# Generated by FakeRAM 2.0
VERSION 5.7 ;
BUSBITCHARS "[]" ;
PROPERTYDEFINITIONS
  MACRO width INTEGER ;
  MACRO depth INTEGER ;
  MACRO banks INTEGER ;
END PROPERTYDEFINITIONS
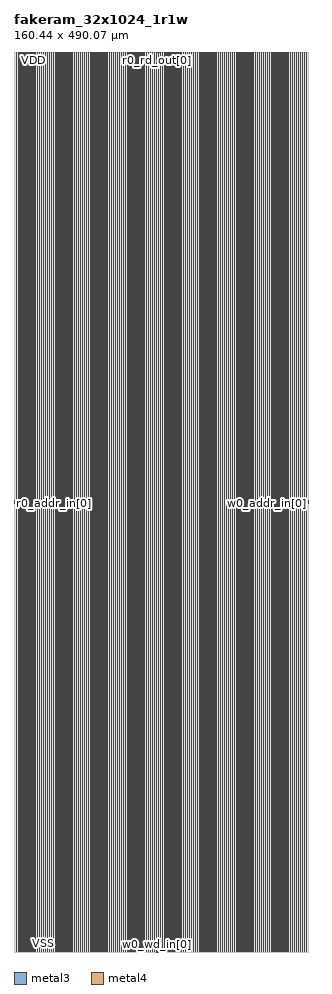
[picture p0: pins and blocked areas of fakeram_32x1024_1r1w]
MACRO fakeram_32x1024_1r1w
  PROPERTY width 32 ;
  PROPERTY depth 1024 ;
  PROPERTY banks 1 ;
  FOREIGN fakeram_32x1024_1r1w 0 0 ;
  SYMMETRY X Y R90 ;
  SIZE 160.440 BY 490.070 ;
  CLASS BLOCK ;
  PIN r0_addr_in[0]
    DIRECTION INPUT ;
    USE SIGNAL ;
    SHAPE ABUTMENT ;
    PORT
      LAYER metal3 ;
      RECT 0.000 244.020 0.070 244.090 ;
    END
  END r0_addr_in[0]
  PIN r0_addr_in[1]
    DIRECTION INPUT ;
    USE SIGNAL ;
    SHAPE ABUTMENT ;
    PORT
      LAYER metal3 ;
      RECT 0.000 244.160 0.070 244.230 ;
    END
  END r0_addr_in[1]
  PIN r0_addr_in[2]
    DIRECTION INPUT ;
    USE SIGNAL ;
    SHAPE ABUTMENT ;
    PORT
      LAYER metal3 ;
      RECT 0.000 244.300 0.070 244.370 ;
    END
  END r0_addr_in[2]
  PIN r0_addr_in[3]
    DIRECTION INPUT ;
    USE SIGNAL ;
    SHAPE ABUTMENT ;
    PORT
      LAYER metal3 ;
      RECT 0.000 244.440 0.070 244.510 ;
    END
  END r0_addr_in[3]
  PIN r0_addr_in[4]
    DIRECTION INPUT ;
    USE SIGNAL ;
    SHAPE ABUTMENT ;
    PORT
      LAYER metal3 ;
      RECT 0.000 244.580 0.070 244.650 ;
    END
  END r0_addr_in[4]
  PIN r0_addr_in[5]
    DIRECTION INPUT ;
    USE SIGNAL ;
    SHAPE ABUTMENT ;
    PORT
      LAYER metal3 ;
      RECT 0.000 244.720 0.070 244.790 ;
    END
  END r0_addr_in[5]
  PIN r0_addr_in[6]
    DIRECTION INPUT ;
    USE SIGNAL ;
    SHAPE ABUTMENT ;
    PORT
      LAYER metal3 ;
      RECT 0.000 244.860 0.070 244.930 ;
    END
  END r0_addr_in[6]
  PIN r0_addr_in[7]
    DIRECTION INPUT ;
    USE SIGNAL ;
    SHAPE ABUTMENT ;
    PORT
      LAYER metal3 ;
      RECT 0.000 245.000 0.070 245.070 ;
    END
  END r0_addr_in[7]
  PIN r0_addr_in[8]
    DIRECTION INPUT ;
    USE SIGNAL ;
    SHAPE ABUTMENT ;
    PORT
      LAYER metal3 ;
      RECT 0.000 245.140 0.070 245.210 ;
    END
  END r0_addr_in[8]
  PIN r0_addr_in[9]
    DIRECTION INPUT ;
    USE SIGNAL ;
    SHAPE ABUTMENT ;
    PORT
      LAYER metal3 ;
      RECT 0.000 245.280 0.070 245.350 ;
    END
  END r0_addr_in[9]
  PIN r0_ce_in
    DIRECTION INPUT ;
    USE SIGNAL ;
    SHAPE ABUTMENT ;
    PORT
      LAYER metal3 ;
      RECT 0.000 245.560 0.070 245.630 ;
    END
  END r0_ce_in
  PIN r0_clk
    DIRECTION INPUT ;
    USE SIGNAL ;
    SHAPE ABUTMENT ;
    PORT
      LAYER metal3 ;
      RECT 0.000 245.700 0.070 245.770 ;
    END
  END r0_clk
  PIN r0_rd_out[0]
    DIRECTION OUTPUT ;
    USE SIGNAL ;
    SHAPE ABUTMENT ;
    PORT
      LAYER metal3 ;
      RECT 77.805 490.000 77.875 490.070 ;
    END
  END r0_rd_out[0]
  PIN r0_rd_out[1]
    DIRECTION OUTPUT ;
    USE SIGNAL ;
    SHAPE ABUTMENT ;
    PORT
      LAYER metal3 ;
      RECT 77.945 490.000 78.015 490.070 ;
    END
  END r0_rd_out[1]
  PIN r0_rd_out[2]
    DIRECTION OUTPUT ;
    USE SIGNAL ;
    SHAPE ABUTMENT ;
    PORT
      LAYER metal3 ;
      RECT 78.085 490.000 78.155 490.070 ;
    END
  END r0_rd_out[2]
  PIN r0_rd_out[3]
    DIRECTION OUTPUT ;
    USE SIGNAL ;
    SHAPE ABUTMENT ;
    PORT
      LAYER metal3 ;
      RECT 78.225 490.000 78.295 490.070 ;
    END
  END r0_rd_out[3]
  PIN r0_rd_out[4]
    DIRECTION OUTPUT ;
    USE SIGNAL ;
    SHAPE ABUTMENT ;
    PORT
      LAYER metal3 ;
      RECT 78.365 490.000 78.435 490.070 ;
    END
  END r0_rd_out[4]
  PIN r0_rd_out[5]
    DIRECTION OUTPUT ;
    USE SIGNAL ;
    SHAPE ABUTMENT ;
    PORT
      LAYER metal3 ;
      RECT 78.505 490.000 78.575 490.070 ;
    END
  END r0_rd_out[5]
  PIN r0_rd_out[6]
    DIRECTION OUTPUT ;
    USE SIGNAL ;
    SHAPE ABUTMENT ;
    PORT
      LAYER metal3 ;
      RECT 78.645 490.000 78.715 490.070 ;
    END
  END r0_rd_out[6]
  PIN r0_rd_out[7]
    DIRECTION OUTPUT ;
    USE SIGNAL ;
    SHAPE ABUTMENT ;
    PORT
      LAYER metal3 ;
      RECT 78.785 490.000 78.855 490.070 ;
    END
  END r0_rd_out[7]
  PIN r0_rd_out[8]
    DIRECTION OUTPUT ;
    USE SIGNAL ;
    SHAPE ABUTMENT ;
    PORT
      LAYER metal3 ;
      RECT 78.925 490.000 78.995 490.070 ;
    END
  END r0_rd_out[8]
  PIN r0_rd_out[9]
    DIRECTION OUTPUT ;
    USE SIGNAL ;
    SHAPE ABUTMENT ;
    PORT
      LAYER metal3 ;
      RECT 79.065 490.000 79.135 490.070 ;
    END
  END r0_rd_out[9]
  PIN r0_rd_out[10]
    DIRECTION OUTPUT ;
    USE SIGNAL ;
    SHAPE ABUTMENT ;
    PORT
      LAYER metal3 ;
      RECT 79.205 490.000 79.275 490.070 ;
    END
  END r0_rd_out[10]
  PIN r0_rd_out[11]
    DIRECTION OUTPUT ;
    USE SIGNAL ;
    SHAPE ABUTMENT ;
    PORT
      LAYER metal3 ;
      RECT 79.345 490.000 79.415 490.070 ;
    END
  END r0_rd_out[11]
  PIN r0_rd_out[12]
    DIRECTION OUTPUT ;
    USE SIGNAL ;
    SHAPE ABUTMENT ;
    PORT
      LAYER metal3 ;
      RECT 79.485 490.000 79.555 490.070 ;
    END
  END r0_rd_out[12]
  PIN r0_rd_out[13]
    DIRECTION OUTPUT ;
    USE SIGNAL ;
    SHAPE ABUTMENT ;
    PORT
      LAYER metal3 ;
      RECT 79.625 490.000 79.695 490.070 ;
    END
  END r0_rd_out[13]
  PIN r0_rd_out[14]
    DIRECTION OUTPUT ;
    USE SIGNAL ;
    SHAPE ABUTMENT ;
    PORT
      LAYER metal3 ;
      RECT 79.765 490.000 79.835 490.070 ;
    END
  END r0_rd_out[14]
  PIN r0_rd_out[15]
    DIRECTION OUTPUT ;
    USE SIGNAL ;
    SHAPE ABUTMENT ;
    PORT
      LAYER metal3 ;
      RECT 79.905 490.000 79.975 490.070 ;
    END
  END r0_rd_out[15]
  PIN r0_rd_out[16]
    DIRECTION OUTPUT ;
    USE SIGNAL ;
    SHAPE ABUTMENT ;
    PORT
      LAYER metal3 ;
      RECT 80.045 490.000 80.115 490.070 ;
    END
  END r0_rd_out[16]
  PIN r0_rd_out[17]
    DIRECTION OUTPUT ;
    USE SIGNAL ;
    SHAPE ABUTMENT ;
    PORT
      LAYER metal3 ;
      RECT 80.185 490.000 80.255 490.070 ;
    END
  END r0_rd_out[17]
  PIN r0_rd_out[18]
    DIRECTION OUTPUT ;
    USE SIGNAL ;
    SHAPE ABUTMENT ;
    PORT
      LAYER metal3 ;
      RECT 80.325 490.000 80.395 490.070 ;
    END
  END r0_rd_out[18]
  PIN r0_rd_out[19]
    DIRECTION OUTPUT ;
    USE SIGNAL ;
    SHAPE ABUTMENT ;
    PORT
      LAYER metal3 ;
      RECT 80.465 490.000 80.535 490.070 ;
    END
  END r0_rd_out[19]
  PIN r0_rd_out[20]
    DIRECTION OUTPUT ;
    USE SIGNAL ;
    SHAPE ABUTMENT ;
    PORT
      LAYER metal3 ;
      RECT 80.605 490.000 80.675 490.070 ;
    END
  END r0_rd_out[20]
  PIN r0_rd_out[21]
    DIRECTION OUTPUT ;
    USE SIGNAL ;
    SHAPE ABUTMENT ;
    PORT
      LAYER metal3 ;
      RECT 80.745 490.000 80.815 490.070 ;
    END
  END r0_rd_out[21]
  PIN r0_rd_out[22]
    DIRECTION OUTPUT ;
    USE SIGNAL ;
    SHAPE ABUTMENT ;
    PORT
      LAYER metal3 ;
      RECT 80.885 490.000 80.955 490.070 ;
    END
  END r0_rd_out[22]
  PIN r0_rd_out[23]
    DIRECTION OUTPUT ;
    USE SIGNAL ;
    SHAPE ABUTMENT ;
    PORT
      LAYER metal3 ;
      RECT 81.025 490.000 81.095 490.070 ;
    END
  END r0_rd_out[23]
  PIN r0_rd_out[24]
    DIRECTION OUTPUT ;
    USE SIGNAL ;
    SHAPE ABUTMENT ;
    PORT
      LAYER metal3 ;
      RECT 81.165 490.000 81.235 490.070 ;
    END
  END r0_rd_out[24]
  PIN r0_rd_out[25]
    DIRECTION OUTPUT ;
    USE SIGNAL ;
    SHAPE ABUTMENT ;
    PORT
      LAYER metal3 ;
      RECT 81.305 490.000 81.375 490.070 ;
    END
  END r0_rd_out[25]
  PIN r0_rd_out[26]
    DIRECTION OUTPUT ;
    USE SIGNAL ;
    SHAPE ABUTMENT ;
    PORT
      LAYER metal3 ;
      RECT 81.445 490.000 81.515 490.070 ;
    END
  END r0_rd_out[26]
  PIN r0_rd_out[27]
    DIRECTION OUTPUT ;
    USE SIGNAL ;
    SHAPE ABUTMENT ;
    PORT
      LAYER metal3 ;
      RECT 81.585 490.000 81.655 490.070 ;
    END
  END r0_rd_out[27]
  PIN r0_rd_out[28]
    DIRECTION OUTPUT ;
    USE SIGNAL ;
    SHAPE ABUTMENT ;
    PORT
      LAYER metal3 ;
      RECT 81.725 490.000 81.795 490.070 ;
    END
  END r0_rd_out[28]
  PIN r0_rd_out[29]
    DIRECTION OUTPUT ;
    USE SIGNAL ;
    SHAPE ABUTMENT ;
    PORT
      LAYER metal3 ;
      RECT 81.865 490.000 81.935 490.070 ;
    END
  END r0_rd_out[29]
  PIN r0_rd_out[30]
    DIRECTION OUTPUT ;
    USE SIGNAL ;
    SHAPE ABUTMENT ;
    PORT
      LAYER metal3 ;
      RECT 82.005 490.000 82.075 490.070 ;
    END
  END r0_rd_out[30]
  PIN r0_rd_out[31]
    DIRECTION OUTPUT ;
    USE SIGNAL ;
    SHAPE ABUTMENT ;
    PORT
      LAYER metal3 ;
      RECT 82.145 490.000 82.215 490.070 ;
    END
  END r0_rd_out[31]
  PIN w0_addr_in[0]
    DIRECTION INPUT ;
    USE SIGNAL ;
    SHAPE ABUTMENT ;
    PORT
      LAYER metal3 ;
      RECT 160.370 244.020 160.440 244.090 ;
    END
  END w0_addr_in[0]
  PIN w0_addr_in[1]
    DIRECTION INPUT ;
    USE SIGNAL ;
    SHAPE ABUTMENT ;
    PORT
      LAYER metal3 ;
      RECT 160.370 244.160 160.440 244.230 ;
    END
  END w0_addr_in[1]
  PIN w0_addr_in[2]
    DIRECTION INPUT ;
    USE SIGNAL ;
    SHAPE ABUTMENT ;
    PORT
      LAYER metal3 ;
      RECT 160.370 244.300 160.440 244.370 ;
    END
  END w0_addr_in[2]
  PIN w0_addr_in[3]
    DIRECTION INPUT ;
    USE SIGNAL ;
    SHAPE ABUTMENT ;
    PORT
      LAYER metal3 ;
      RECT 160.370 244.440 160.440 244.510 ;
    END
  END w0_addr_in[3]
  PIN w0_addr_in[4]
    DIRECTION INPUT ;
    USE SIGNAL ;
    SHAPE ABUTMENT ;
    PORT
      LAYER metal3 ;
      RECT 160.370 244.580 160.440 244.650 ;
    END
  END w0_addr_in[4]
  PIN w0_addr_in[5]
    DIRECTION INPUT ;
    USE SIGNAL ;
    SHAPE ABUTMENT ;
    PORT
      LAYER metal3 ;
      RECT 160.370 244.720 160.440 244.790 ;
    END
  END w0_addr_in[5]
  PIN w0_addr_in[6]
    DIRECTION INPUT ;
    USE SIGNAL ;
    SHAPE ABUTMENT ;
    PORT
      LAYER metal3 ;
      RECT 160.370 244.860 160.440 244.930 ;
    END
  END w0_addr_in[6]
  PIN w0_addr_in[7]
    DIRECTION INPUT ;
    USE SIGNAL ;
    SHAPE ABUTMENT ;
    PORT
      LAYER metal3 ;
      RECT 160.370 245.000 160.440 245.070 ;
    END
  END w0_addr_in[7]
  PIN w0_addr_in[8]
    DIRECTION INPUT ;
    USE SIGNAL ;
    SHAPE ABUTMENT ;
    PORT
      LAYER metal3 ;
      RECT 160.370 245.140 160.440 245.210 ;
    END
  END w0_addr_in[8]
  PIN w0_addr_in[9]
    DIRECTION INPUT ;
    USE SIGNAL ;
    SHAPE ABUTMENT ;
    PORT
      LAYER metal3 ;
      RECT 160.370 245.280 160.440 245.350 ;
    END
  END w0_addr_in[9]
  PIN w0_we_in
    DIRECTION INPUT ;
    USE SIGNAL ;
    SHAPE ABUTMENT ;
    PORT
      LAYER metal3 ;
      RECT 160.370 245.560 160.440 245.630 ;
    END
  END w0_we_in
  PIN w0_ce_in
    DIRECTION INPUT ;
    USE SIGNAL ;
    SHAPE ABUTMENT ;
    PORT
      LAYER metal3 ;
      RECT 160.370 245.700 160.440 245.770 ;
    END
  END w0_ce_in
  PIN w0_clk
    DIRECTION INPUT ;
    USE SIGNAL ;
    SHAPE ABUTMENT ;
    PORT
      LAYER metal3 ;
      RECT 160.370 245.840 160.440 245.910 ;
    END
  END w0_clk
  PIN w0_wd_in[0]
    DIRECTION INPUT ;
    USE SIGNAL ;
    SHAPE ABUTMENT ;
    PORT
      LAYER metal3 ;
      RECT 77.805 0.000 77.875 0.070 ;
    END
  END w0_wd_in[0]
  PIN w0_wd_in[1]
    DIRECTION INPUT ;
    USE SIGNAL ;
    SHAPE ABUTMENT ;
    PORT
      LAYER metal3 ;
      RECT 77.945 0.000 78.015 0.070 ;
    END
  END w0_wd_in[1]
  PIN w0_wd_in[2]
    DIRECTION INPUT ;
    USE SIGNAL ;
    SHAPE ABUTMENT ;
    PORT
      LAYER metal3 ;
      RECT 78.085 0.000 78.155 0.070 ;
    END
  END w0_wd_in[2]
  PIN w0_wd_in[3]
    DIRECTION INPUT ;
    USE SIGNAL ;
    SHAPE ABUTMENT ;
    PORT
      LAYER metal3 ;
      RECT 78.225 0.000 78.295 0.070 ;
    END
  END w0_wd_in[3]
  PIN w0_wd_in[4]
    DIRECTION INPUT ;
    USE SIGNAL ;
    SHAPE ABUTMENT ;
    PORT
      LAYER metal3 ;
      RECT 78.365 0.000 78.435 0.070 ;
    END
  END w0_wd_in[4]
  PIN w0_wd_in[5]
    DIRECTION INPUT ;
    USE SIGNAL ;
    SHAPE ABUTMENT ;
    PORT
      LAYER metal3 ;
      RECT 78.505 0.000 78.575 0.070 ;
    END
  END w0_wd_in[5]
  PIN w0_wd_in[6]
    DIRECTION INPUT ;
    USE SIGNAL ;
    SHAPE ABUTMENT ;
    PORT
      LAYER metal3 ;
      RECT 78.645 0.000 78.715 0.070 ;
    END
  END w0_wd_in[6]
  PIN w0_wd_in[7]
    DIRECTION INPUT ;
    USE SIGNAL ;
    SHAPE ABUTMENT ;
    PORT
      LAYER metal3 ;
      RECT 78.785 0.000 78.855 0.070 ;
    END
  END w0_wd_in[7]
  PIN w0_wd_in[8]
    DIRECTION INPUT ;
    USE SIGNAL ;
    SHAPE ABUTMENT ;
    PORT
      LAYER metal3 ;
      RECT 78.925 0.000 78.995 0.070 ;
    END
  END w0_wd_in[8]
  PIN w0_wd_in[9]
    DIRECTION INPUT ;
    USE SIGNAL ;
    SHAPE ABUTMENT ;
    PORT
      LAYER metal3 ;
      RECT 79.065 0.000 79.135 0.070 ;
    END
  END w0_wd_in[9]
  PIN w0_wd_in[10]
    DIRECTION INPUT ;
    USE SIGNAL ;
    SHAPE ABUTMENT ;
    PORT
      LAYER metal3 ;
      RECT 79.205 0.000 79.275 0.070 ;
    END
  END w0_wd_in[10]
  PIN w0_wd_in[11]
    DIRECTION INPUT ;
    USE SIGNAL ;
    SHAPE ABUTMENT ;
    PORT
      LAYER metal3 ;
      RECT 79.345 0.000 79.415 0.070 ;
    END
  END w0_wd_in[11]
  PIN w0_wd_in[12]
    DIRECTION INPUT ;
    USE SIGNAL ;
    SHAPE ABUTMENT ;
    PORT
      LAYER metal3 ;
      RECT 79.485 0.000 79.555 0.070 ;
    END
  END w0_wd_in[12]
  PIN w0_wd_in[13]
    DIRECTION INPUT ;
    USE SIGNAL ;
    SHAPE ABUTMENT ;
    PORT
      LAYER metal3 ;
      RECT 79.625 0.000 79.695 0.070 ;
    END
  END w0_wd_in[13]
  PIN w0_wd_in[14]
    DIRECTION INPUT ;
    USE SIGNAL ;
    SHAPE ABUTMENT ;
    PORT
      LAYER metal3 ;
      RECT 79.765 0.000 79.835 0.070 ;
    END
  END w0_wd_in[14]
  PIN w0_wd_in[15]
    DIRECTION INPUT ;
    USE SIGNAL ;
    SHAPE ABUTMENT ;
    PORT
      LAYER metal3 ;
      RECT 79.905 0.000 79.975 0.070 ;
    END
  END w0_wd_in[15]
  PIN w0_wd_in[16]
    DIRECTION INPUT ;
    USE SIGNAL ;
    SHAPE ABUTMENT ;
    PORT
      LAYER metal3 ;
      RECT 80.045 0.000 80.115 0.070 ;
    END
  END w0_wd_in[16]
  PIN w0_wd_in[17]
    DIRECTION INPUT ;
    USE SIGNAL ;
    SHAPE ABUTMENT ;
    PORT
      LAYER metal3 ;
      RECT 80.185 0.000 80.255 0.070 ;
    END
  END w0_wd_in[17]
  PIN w0_wd_in[18]
    DIRECTION INPUT ;
    USE SIGNAL ;
    SHAPE ABUTMENT ;
    PORT
      LAYER metal3 ;
      RECT 80.325 0.000 80.395 0.070 ;
    END
  END w0_wd_in[18]
  PIN w0_wd_in[19]
    DIRECTION INPUT ;
    USE SIGNAL ;
    SHAPE ABUTMENT ;
    PORT
      LAYER metal3 ;
      RECT 80.465 0.000 80.535 0.070 ;
    END
  END w0_wd_in[19]
  PIN w0_wd_in[20]
    DIRECTION INPUT ;
    USE SIGNAL ;
    SHAPE ABUTMENT ;
    PORT
      LAYER metal3 ;
      RECT 80.605 0.000 80.675 0.070 ;
    END
  END w0_wd_in[20]
  PIN w0_wd_in[21]
    DIRECTION INPUT ;
    USE SIGNAL ;
    SHAPE ABUTMENT ;
    PORT
      LAYER metal3 ;
      RECT 80.745 0.000 80.815 0.070 ;
    END
  END w0_wd_in[21]
  PIN w0_wd_in[22]
    DIRECTION INPUT ;
    USE SIGNAL ;
    SHAPE ABUTMENT ;
    PORT
      LAYER metal3 ;
      RECT 80.885 0.000 80.955 0.070 ;
    END
  END w0_wd_in[22]
  PIN w0_wd_in[23]
    DIRECTION INPUT ;
    USE SIGNAL ;
    SHAPE ABUTMENT ;
    PORT
      LAYER metal3 ;
      RECT 81.025 0.000 81.095 0.070 ;
    END
  END w0_wd_in[23]
  PIN w0_wd_in[24]
    DIRECTION INPUT ;
    USE SIGNAL ;
    SHAPE ABUTMENT ;
    PORT
      LAYER metal3 ;
      RECT 81.165 0.000 81.235 0.070 ;
    END
  END w0_wd_in[24]
  PIN w0_wd_in[25]
    DIRECTION INPUT ;
    USE SIGNAL ;
    SHAPE ABUTMENT ;
    PORT
      LAYER metal3 ;
      RECT 81.305 0.000 81.375 0.070 ;
    END
  END w0_wd_in[25]
  PIN w0_wd_in[26]
    DIRECTION INPUT ;
    USE SIGNAL ;
    SHAPE ABUTMENT ;
    PORT
      LAYER metal3 ;
      RECT 81.445 0.000 81.515 0.070 ;
    END
  END w0_wd_in[26]
  PIN w0_wd_in[27]
    DIRECTION INPUT ;
    USE SIGNAL ;
    SHAPE ABUTMENT ;
    PORT
      LAYER metal3 ;
      RECT 81.585 0.000 81.655 0.070 ;
    END
  END w0_wd_in[27]
  PIN w0_wd_in[28]
    DIRECTION INPUT ;
    USE SIGNAL ;
    SHAPE ABUTMENT ;
    PORT
      LAYER metal3 ;
      RECT 81.725 0.000 81.795 0.070 ;
    END
  END w0_wd_in[28]
  PIN w0_wd_in[29]
    DIRECTION INPUT ;
    USE SIGNAL ;
    SHAPE ABUTMENT ;
    PORT
      LAYER metal3 ;
      RECT 81.865 0.000 81.935 0.070 ;
    END
  END w0_wd_in[29]
  PIN w0_wd_in[30]
    DIRECTION INPUT ;
    USE SIGNAL ;
    SHAPE ABUTMENT ;
    PORT
      LAYER metal3 ;
      RECT 82.005 0.000 82.075 0.070 ;
    END
  END w0_wd_in[30]
  PIN w0_wd_in[31]
    DIRECTION INPUT ;
    USE SIGNAL ;
    SHAPE ABUTMENT ;
    PORT
      LAYER metal3 ;
      RECT 82.145 0.000 82.215 0.070 ;
    END
  END w0_wd_in[31]
  PIN VSS
    DIRECTION INOUT ;
    USE GROUND ;
    PORT
      LAYER metal4 ;
      RECT 2.450 0.140 2.730 489.930 ;
      RECT 4.690 0.140 4.970 489.930 ;
      RECT 6.930 0.140 7.210 489.930 ;
      RECT 9.170 0.140 9.450 489.930 ;
      RECT 11.410 0.140 11.690 489.930 ;
      RECT 13.650 0.140 13.930 489.930 ;
      RECT 15.890 0.140 16.170 489.930 ;
      RECT 18.130 0.140 18.410 489.930 ;
      RECT 20.370 0.140 20.650 489.930 ;
      RECT 22.610 0.140 22.890 489.930 ;
      RECT 24.850 0.140 25.130 489.930 ;
      RECT 27.090 0.140 27.370 489.930 ;
      RECT 29.330 0.140 29.610 489.930 ;
      RECT 31.570 0.140 31.850 489.930 ;
      RECT 33.810 0.140 34.090 489.930 ;
      RECT 36.050 0.140 36.330 489.930 ;
      RECT 38.290 0.140 38.570 489.930 ;
      RECT 40.530 0.140 40.810 489.930 ;
      RECT 42.770 0.140 43.050 489.930 ;
      RECT 45.010 0.140 45.290 489.930 ;
      RECT 47.250 0.140 47.530 489.930 ;
      RECT 49.490 0.140 49.770 489.930 ;
      RECT 51.730 0.140 52.010 489.930 ;
      RECT 53.970 0.140 54.250 489.930 ;
      RECT 56.210 0.140 56.490 489.930 ;
      RECT 58.450 0.140 58.730 489.930 ;
      RECT 60.690 0.140 60.970 489.930 ;
      RECT 62.930 0.140 63.210 489.930 ;
      RECT 65.170 0.140 65.450 489.930 ;
      RECT 67.410 0.140 67.690 489.930 ;
      RECT 69.650 0.140 69.930 489.930 ;
      RECT 71.890 0.140 72.170 489.930 ;
      RECT 74.130 0.140 74.410 489.930 ;
      RECT 76.370 0.140 76.650 489.930 ;
      RECT 78.610 0.140 78.890 489.930 ;
      RECT 80.850 0.140 81.130 489.930 ;
      RECT 83.090 0.140 83.370 489.930 ;
      RECT 85.330 0.140 85.610 489.930 ;
      RECT 87.570 0.140 87.850 489.930 ;
      RECT 89.810 0.140 90.090 489.930 ;
      RECT 92.050 0.140 92.330 489.930 ;
      RECT 94.290 0.140 94.570 489.930 ;
      RECT 96.530 0.140 96.810 489.930 ;
      RECT 98.770 0.140 99.050 489.930 ;
      RECT 101.010 0.140 101.290 489.930 ;
      RECT 103.250 0.140 103.530 489.930 ;
      RECT 105.490 0.140 105.770 489.930 ;
      RECT 107.730 0.140 108.010 489.930 ;
      RECT 109.970 0.140 110.250 489.930 ;
      RECT 112.210 0.140 112.490 489.930 ;
      RECT 114.450 0.140 114.730 489.930 ;
      RECT 116.690 0.140 116.970 489.930 ;
      RECT 118.930 0.140 119.210 489.930 ;
      RECT 121.170 0.140 121.450 489.930 ;
      RECT 123.410 0.140 123.690 489.930 ;
      RECT 125.650 0.140 125.930 489.930 ;
      RECT 127.890 0.140 128.170 489.930 ;
      RECT 130.130 0.140 130.410 489.930 ;
      RECT 132.370 0.140 132.650 489.930 ;
      RECT 134.610 0.140 134.890 489.930 ;
      RECT 136.850 0.140 137.130 489.930 ;
      RECT 139.090 0.140 139.370 489.930 ;
      RECT 141.330 0.140 141.610 489.930 ;
      RECT 143.570 0.140 143.850 489.930 ;
      RECT 145.810 0.140 146.090 489.930 ;
      RECT 148.050 0.140 148.330 489.930 ;
      RECT 150.290 0.140 150.570 489.930 ;
      RECT 152.530 0.140 152.810 489.930 ;
      RECT 154.770 0.140 155.050 489.930 ;
      RECT 157.010 0.140 157.290 489.930 ;
      RECT 159.250 0.140 159.530 489.930 ;
    END
  END VSS
  PIN VDD
    DIRECTION INOUT ;
    USE POWER ;
    PORT
      LAYER metal4 ;
      RECT 1.330 0.140 1.610 489.930 ;
      RECT 3.570 0.140 3.850 489.930 ;
      RECT 5.810 0.140 6.090 489.930 ;
      RECT 8.050 0.140 8.330 489.930 ;
      RECT 10.290 0.140 10.570 489.930 ;
      RECT 12.530 0.140 12.810 489.930 ;
      RECT 14.770 0.140 15.050 489.930 ;
      RECT 17.010 0.140 17.290 489.930 ;
      RECT 19.250 0.140 19.530 489.930 ;
      RECT 21.490 0.140 21.770 489.930 ;
      RECT 23.730 0.140 24.010 489.930 ;
      RECT 25.970 0.140 26.250 489.930 ;
      RECT 28.210 0.140 28.490 489.930 ;
      RECT 30.450 0.140 30.730 489.930 ;
      RECT 32.690 0.140 32.970 489.930 ;
      RECT 34.930 0.140 35.210 489.930 ;
      RECT 37.170 0.140 37.450 489.930 ;
      RECT 39.410 0.140 39.690 489.930 ;
      RECT 41.650 0.140 41.930 489.930 ;
      RECT 43.890 0.140 44.170 489.930 ;
      RECT 46.130 0.140 46.410 489.930 ;
      RECT 48.370 0.140 48.650 489.930 ;
      RECT 50.610 0.140 50.890 489.930 ;
      RECT 52.850 0.140 53.130 489.930 ;
      RECT 55.090 0.140 55.370 489.930 ;
      RECT 57.330 0.140 57.610 489.930 ;
      RECT 59.570 0.140 59.850 489.930 ;
      RECT 61.810 0.140 62.090 489.930 ;
      RECT 64.050 0.140 64.330 489.930 ;
      RECT 66.290 0.140 66.570 489.930 ;
      RECT 68.530 0.140 68.810 489.930 ;
      RECT 70.770 0.140 71.050 489.930 ;
      RECT 73.010 0.140 73.290 489.930 ;
      RECT 75.250 0.140 75.530 489.930 ;
      RECT 77.490 0.140 77.770 489.930 ;
      RECT 79.730 0.140 80.010 489.930 ;
      RECT 81.970 0.140 82.250 489.930 ;
      RECT 84.210 0.140 84.490 489.930 ;
      RECT 86.450 0.140 86.730 489.930 ;
      RECT 88.690 0.140 88.970 489.930 ;
      RECT 90.930 0.140 91.210 489.930 ;
      RECT 93.170 0.140 93.450 489.930 ;
      RECT 95.410 0.140 95.690 489.930 ;
      RECT 97.650 0.140 97.930 489.930 ;
      RECT 99.890 0.140 100.170 489.930 ;
      RECT 102.130 0.140 102.410 489.930 ;
      RECT 104.370 0.140 104.650 489.930 ;
      RECT 106.610 0.140 106.890 489.930 ;
      RECT 108.850 0.140 109.130 489.930 ;
      RECT 111.090 0.140 111.370 489.930 ;
      RECT 113.330 0.140 113.610 489.930 ;
      RECT 115.570 0.140 115.850 489.930 ;
      RECT 117.810 0.140 118.090 489.930 ;
      RECT 120.050 0.140 120.330 489.930 ;
      RECT 122.290 0.140 122.570 489.930 ;
      RECT 124.530 0.140 124.810 489.930 ;
      RECT 126.770 0.140 127.050 489.930 ;
      RECT 129.010 0.140 129.290 489.930 ;
      RECT 131.250 0.140 131.530 489.930 ;
      RECT 133.490 0.140 133.770 489.930 ;
      RECT 135.730 0.140 136.010 489.930 ;
      RECT 137.970 0.140 138.250 489.930 ;
      RECT 140.210 0.140 140.490 489.930 ;
      RECT 142.450 0.140 142.730 489.930 ;
      RECT 144.690 0.140 144.970 489.930 ;
      RECT 146.930 0.140 147.210 489.930 ;
      RECT 149.170 0.140 149.450 489.930 ;
      RECT 151.410 0.140 151.690 489.930 ;
      RECT 153.650 0.140 153.930 489.930 ;
      RECT 155.890 0.140 156.170 489.930 ;
      RECT 158.130 0.140 158.410 489.930 ;
    END
  END VDD
  OBS
    LAYER metal1 ;
    RECT 0 0 160.440 490.070 ;
    LAYER metal2 ;
    RECT 0 0 160.440 490.070 ;
    LAYER metal3 ;
    RECT 0 0 160.440 490.070 ;
    LAYER metal4 ;
    RECT 0 0 160.440 490.070 ;
    LAYER OVERLAP ;
    RECT 0 0 160.440 490.070 ;
  END
END fakeram_32x1024_1r1w

END LIBRARY
